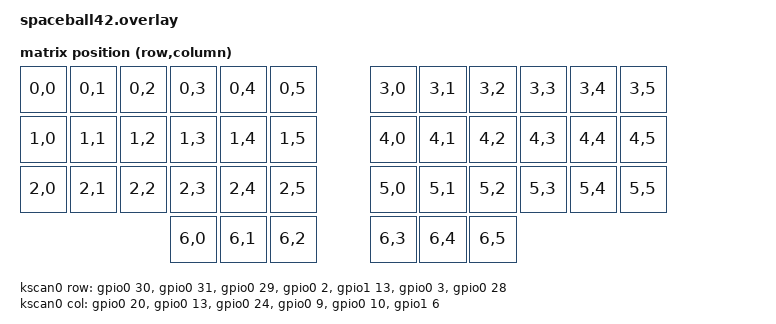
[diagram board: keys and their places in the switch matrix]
/*
 * Copyright (c) 2020 The ZMK Contributors
 *
 * SPDX-License-Identifier: MIT
 */

#include <dt-bindings/zmk/matrix_transform.h>

/ {
    chosen {
        zmk,kscan = &kscan0;
        zmk,matrix_transform = &default_transform;
    };

    default_transform: keymap_transform_0 {
        compatible = "zmk,matrix-transform";
        columns = <6>;
        rows = <7>;

        map = <
RC(0,0) RC(0,1) RC(0,2) RC(0,3) RC(0,4) RC(0,5) RC(3,0) RC(3,1) RC(3,2) RC(3,3) RC(3,4) RC(3,5)
RC(1,0) RC(1,1) RC(1,2) RC(1,3) RC(1,4) RC(1,5) RC(4,0) RC(4,1) RC(4,2) RC(4,3) RC(4,4) RC(4,5)
RC(2,0) RC(2,1) RC(2,2) RC(2,3) RC(2,4) RC(2,5) RC(5,0) RC(5,1) RC(5,2) RC(5,3) RC(5,4) RC(5,5)
                        RC(6,0) RC(6,1) RC(6,2) RC(6,3) RC(6,4) RC(6,5)
        >;
    };

    kscan0: kscan_0 {
        compatible = "zmk,kscan-gpio-matrix";
        label = "KSCAN";
        diode-direction = "col2row";

        col-gpios
            = <&gpio0 20 GPIO_ACTIVE_HIGH>
            , <&gpio0 13 GPIO_ACTIVE_HIGH>
            , <&gpio0 24 GPIO_ACTIVE_HIGH>
            , <&gpio0 9 GPIO_ACTIVE_HIGH>
            , <&gpio0 10 GPIO_ACTIVE_HIGH>
            , <&gpio1 6 GPIO_ACTIVE_HIGH>
            ;

        row-gpios
            = <&gpio0 30 (GPIO_ACTIVE_HIGH | GPIO_PULL_DOWN)>
            , <&gpio0 31 (GPIO_ACTIVE_HIGH | GPIO_PULL_DOWN)>
            , <&gpio0 29 (GPIO_ACTIVE_HIGH | GPIO_PULL_DOWN)>
            , <&gpio0 2 (GPIO_ACTIVE_HIGH | GPIO_PULL_DOWN)>
            , <&gpio1 13 (GPIO_ACTIVE_HIGH | GPIO_PULL_DOWN)>
            , <&gpio0 3 (GPIO_ACTIVE_HIGH | GPIO_PULL_DOWN)>
            , <&gpio0 28 (GPIO_ACTIVE_HIGH | GPIO_PULL_DOWN)>
            ;
    };
    
    trackballs {
	compatible = "zmk,keymap-trackballs";
	trackballs = <&trackball>;
    };
};

&spi0 {
	compatible = "nordic,nrf-spim";
	status = "disabled";

	trackball: trackball@0 {
		compatible = "pixart,pmw3610";
		status = "disabled";
		reg = <0>;
		label = "TRACKBALL";
		spi-max-frequency = <2000000>;
		duplex = <2048>; // required by 3-wire spi
	};
};

// trackball bus
&spi0 {
	status = "okay"; //okay
	sck-pin = <17>;
	mosi-pin = <12>;
	miso-pin = <12>; // same as mosi (3-wire spi)
	cs-gpios = <&gpio0 22 GPIO_ACTIVE_LOW>;
};

&trackball {
	status = "okay"; //okay
	irq-gpios = <&gpio0 7 (GPIO_ACTIVE_LOW | GPIO_PULL_UP)>;
};

/*
&pinctrl {
    spi0_default: spi0_default {
        group1 {
            psels = <NRF_PSEL(SPIM_SCK, 0, 17)>,
                    <NRF_PSEL(SPIM_MOSI, 0, 12)>,
                    <NRF_PSEL(SPIM_MISO, 0, 12)>;
        };
    };
    
    spi0_sleep: spi0_sleep {
        group1 {
            psels = <NRF_PSEL(SPIM_SCK, 0, 17)>,
                    <NRF_PSEL(SPIM_MOSI, 0, 12)>,
                    <NRF_PSEL(SPIM_MISO, 0, 12)>;
                low-power-enable;
        };
    };
};
    
&spi0 {
    status = "okay";
    compatible = "nordic,nrf-spim";
    pinctrl-0 = <&spi0_default>;
    pinctrl-1 = <&spi0_sleep>;
    pinctrl-names = "default", "sleep";
    cs-gpios = <&gpio0 22 GPIO_ACTIVE_LOW>;
    
    trackball: trackball@0 {
        status = "okay";
        compatible = "pixart,pmw3610";
        reg = <0>;
        spi-max-frequency = <2000000>;
        irq-gpios = <&gpio0 7 (GPIO_ACTIVE_LOW | GPIO_PULL_UP)>;
    
        /*   optional features   */
        // snipe-layers = <1>;
        // scroll-layers = <2 3>;
        // automouse-layer = <4>;
    };
};
*/
